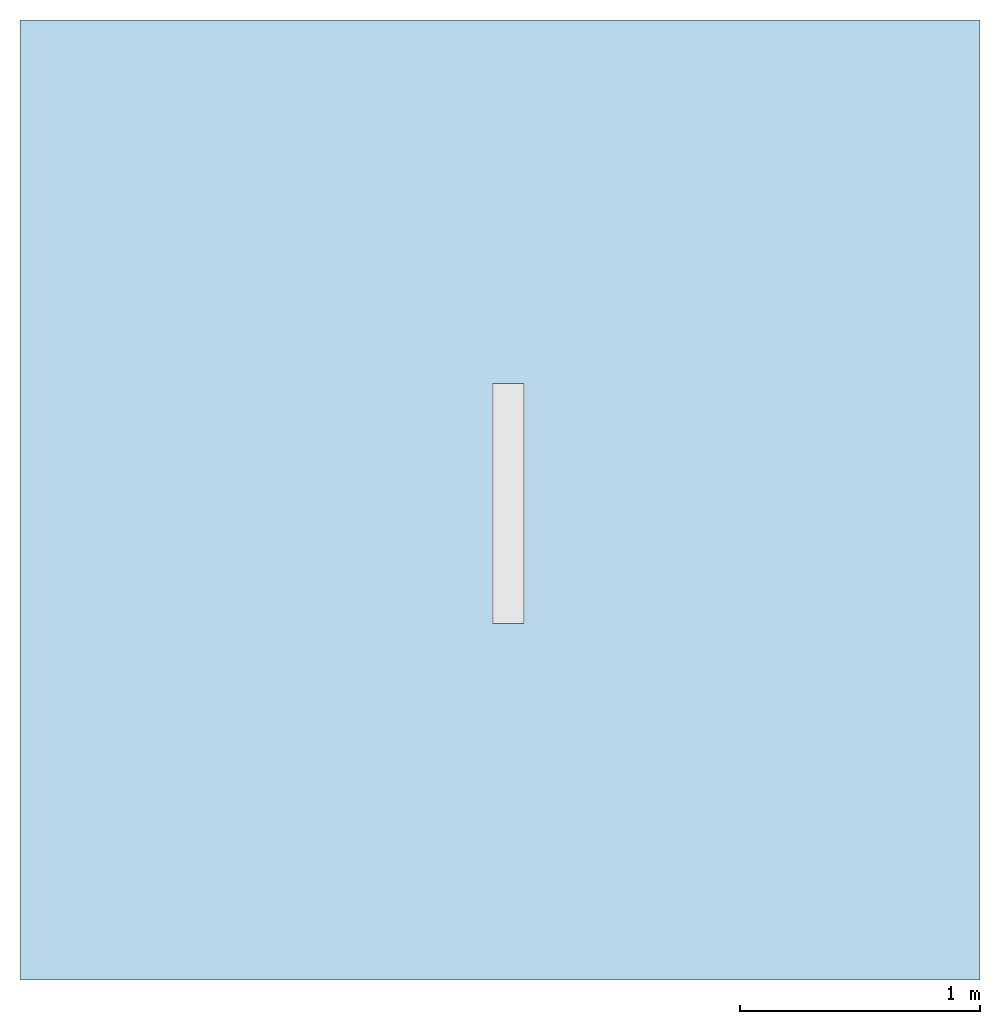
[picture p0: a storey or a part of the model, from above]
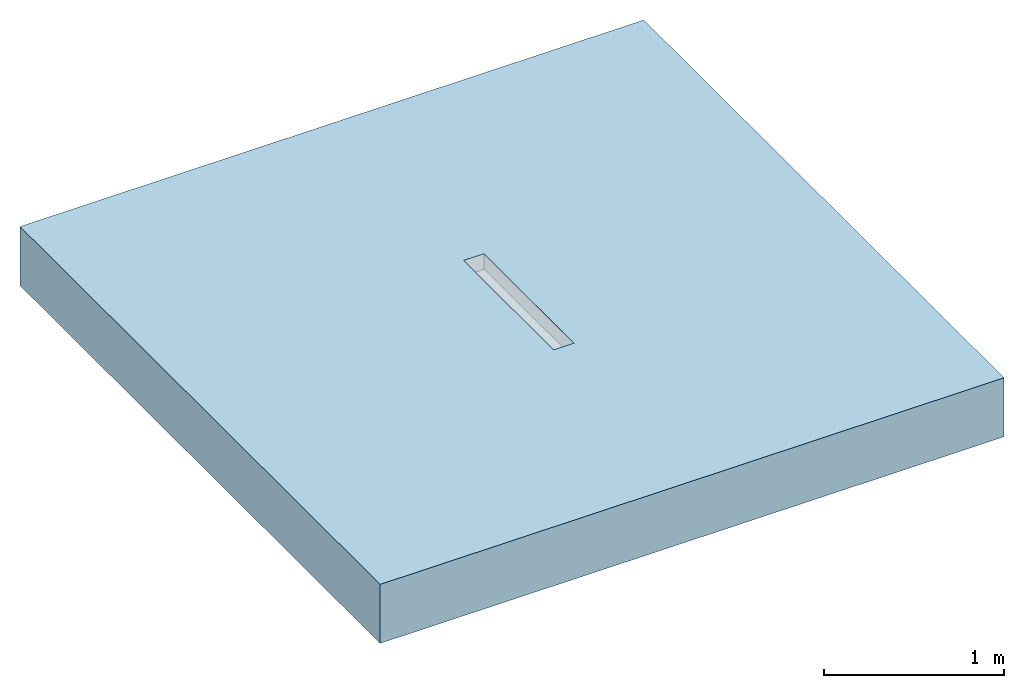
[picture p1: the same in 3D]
Properties of the parts of a building model (IFC2X3)

# File
Description: ViewDefinition [CoordinationView]
File name: Project Number
Time: 2014-06-06T14:24:36
Written by: The EXPRESS Data Manager Version 5.01.0100.02.64mod : 6 Jun 2012
Made in: 20130308_1515(x64) - Exporter 2014.0.2013.0308 - Default UI
Comment: STEP Physical File produced by: The EXPRESS Data Manager Version 5.01.0100.02.64mod : 6 Jun 2012 * Module: EDMstepFileFactory/EDMstandAlone * Creation date: Fri Jun 06 14:24:36 2014 * Host: IN-BLR-PC-0010 * Database: C:\Users\palleri\AppData\Local\Temp\{B5368119-474E-4063-B5B9-858C72C87719}\ifc * Database version: 5507 * Database creation date: Fri Jun 06 14:24:35 2014 * Schema: IFC2X3 * Model: DataRepository.ifc * Model creation date: Fri Jun 06 14:24:35 2014 * Header model: DataRepository.ifc_HeaderModel * Header model creation date: Fri Jun 06 14:24:35 2014 * EDMuser: sdai-user * EDMgroup: sdai-group * License ID and type: 5605 : Permanent license. Expiry date: * EDMstepFileFactory options: 020000

# IfcProject, Project Number
LongName: Project Name; Phase: Project Status

# IfcSite, Default
RefLatitude: 42, 21, 30, 344238; RefLongitude: -71, -3, -35, -194702; RefElevation: 0 mm

# IfcBuilding
Pset_BuildingCommon - NumberOfStoreys: 1
Other - Project Number: Project Number; Project Address: ## Street City, State Zip; Client Name: Owner; Project Status: Project Status; Project Issue Date: Issue Date; Project Name: Project Name

# IfcBuildingStorey, Level 1
LongName: Level 1; Elevation: 0 mm
Constraints - Elevation Base: Project Base Point; Elevation: 0 mm
Graphics - Symbol at End 1 Default: no; Color: 0; Symbol: M_Level Head - Circle: M_Level Head - Circle; Line Weight: 1; Symbol at End 2 Default: yes; Line Pattern: Center
Dimensions - Computation Height: 0 mm
Identity Data - Name: Level 1; Building Story: yes; Structural: no

# IfcFlowTerminal: 36836 - Adjustable Channel - Intermediate Section - 1000mm LG - Invert Depth 75/105mm, ACO Freedeck Adjustable Height Channel Intermediate Section Stainless Steel:36836 - Adjustable Channel - Intermediate Section - 1000mm LG - Invert Depth 75/105mm:313968
In: Level 1
Material: Stainless Steel Grade 304
Construction - End Plate Invert 2: no; 36955 - Grating - Plain Mesh - Stainless Steel 304 - 1000mm long: yes; 36954 - Grating - Plain Mesh - Stainless Steel 304 - 500mm long: no; 00272 - Grating - Slotted Grating - Stainless Steel 304 - 1000mm long: no; End Plate Invert 1: no; 00273 - Grating - Slotted Grating - Stainless Steel 304 - 500mm long: no
Dimensions - Height @ Invert 1 (75 - 105mm): 105 mm; Height @ Invert 2 (75 - 105mm): 105 mm; Channel End Length: -1000 mm; Grating End Length: 1000 mm
Constraints - Moves With Nearby Elements: no; Level: Level: Level 1
Phasing - Phase Created: New Construction
Other - Height @ Invert 2 Min & Max: 105 mm; Top Piece Void Height @ Invert 1: 45 mm; Top Piece Void Height @ Invert 2: 45 mm; Height @ Invert 1 Min & Max: 105 mm; Nos: 32
Identity Data - Mark: 29; Watermark1: This file is the property of ACO Technologies PLC; Fax: +44 (0)1462 851490; Telephone: +44 (0)1462 816666; Manufacturer: ACO Building Drainage; E-mail Technical: abdtechnical@aco.co.uk; Website: www.acobd.com; Watermarked By: www.acobd.com; E-mail Sales: abdcommercial@aco.co.uk; Watermark2: This file is water marked and users are prohibited to reproduce, adapt, distribute this information; Address: ACO Business Centre, Caxton Road, Bedford, MK41 0LF; Watermarked With: BIM Manager Premium Suite
Pset_ManufacturerTypeInformation - Manufacturer: ACO Building Drainage
General - Load Class: A15; Price: POA - contact ACO; NBS Specification: NBS Section R10 Gravity Rainwater Drainage Systems, Subsection 365; Dimensions (LxWxH): 1000 x 130 x 75/105; Channel Recyclable: Fully recyclable; Maintenance Guidelines: X:\Electronic Literature\ABD Electronic Literature\Roof and Balcony Drainage\ACO Freedeck Brochure.pdf; Installation Guidelines: X:\Electronic Literature\ABD Electronic Literature\Roof and Balcony Drainage\ACO Freedeck Brochure.pdf; Product Type: Linear Deck Drainage System; Channel Colour: Mid Grey; Product Standard: BS EN 1433:2002, CE marked; Product Code: 36836; Channel Material: Stainless Steel Grade 304; Channel Recycled Material Content: 60 - 70 %; Product Description: ACO Freedeck Adjustable Channel - Intermediate Section; Weight (Kg): 5.4kg; Product Range: ACO Freedeck
Model Properties - Grating Product Code 36955: Load Class A15 - Mesh Grating - 14mm x 30mm Mesh - Stainless Steel 304 - 1000mm long - 3.0kg; Grating Product Code 00272: Load Class A15 - Slotted Grating - 10 x 80mm Slot - Stainless Steel 304 - 1000mm long - 2.2kg; Grating Product Code 36954: Load Class A15 - Mesh Grating - 14mm x 30mm Mesh - Stainless Steel 304 - 500mm long - 1.6kg; End Plate Product Code 36841: End Plate Stainless Steel 304 for Invert Depth - 75/105mm - 0.1Kg; Grating Product Code 00273: Load Class A15 - Slotted Grating - 10 x 80mm Slot - Stainless Steel 304 - 500mm long - 1.0kg
Materials and Finishes - Material: Stainless Steel Grade 304

# IfcOpeningElement: Recess
In: Level 1
Structural - Enable Analytical Model: no; Structural: no
Constraints - Height Offset From Level: 0 mm; Related to Mass: no; Room Bounding: yes; Level: Level: Level 1
Dimensions - Area: 16 m2; Perimeter: 16000 mm; Volume: 6.38611 m3; Thickness: 400 mm
Phasing - Phase Created: New Construction
Analytical Properties - Absorptance: 0.1; Thermal mass: 604440; Roughness: 1; Heat Transfer Coefficient (U): 2.615; Thermal Resistance (R): 0.382409
Materials and Finishes - Structural Material: Concrete, Broom Finish
Construction - Function: Interior; Default Thickness: 400 mm
Graphics - Coarse Scale Fill Color: 0

# IfcSlab: Floor:Generic Floor - 400mm, Floor:Generic Floor - 400mm:193825
In: Level 1
PredefinedType: FLOOR; Material: Concrete, Broom Finish 400 mm
Structural - Enable Analytical Model: no; Structural: no
Constraints - Height Offset From Level: 0 mm; Related to Mass: no; Room Bounding: yes; Level: Level: Level 1
Dimensions - Area: 16 m2; Perimeter: 16000 mm; Volume: 6.38611 m3; Thickness: 400 mm
Phasing - Phase Created: New Construction
Pset_SlabCommon - Reference: Generic Floor - 400mm; IsExternal: no; LoadBearing: yes; ThermalTransmittance: 2.615 kg/K/s3
Analytical Properties - Absorptance: 0.1; Thermal mass: 604440; Roughness: 1; Heat Transfer Coefficient (U): 2.615; Thermal Resistance (R): 0.382409
Materials and Finishes - Structural Material: Concrete, Broom Finish
Construction - Function: Interior; Default Thickness: 400 mm
Graphics - Coarse Scale Fill Color: 0
